VERSION 5.7 ;
  NOWIREEXTENSIONATPIN ON ;
  DIVIDERCHAR "/" ;
  BUSBITCHARS "[]" ;
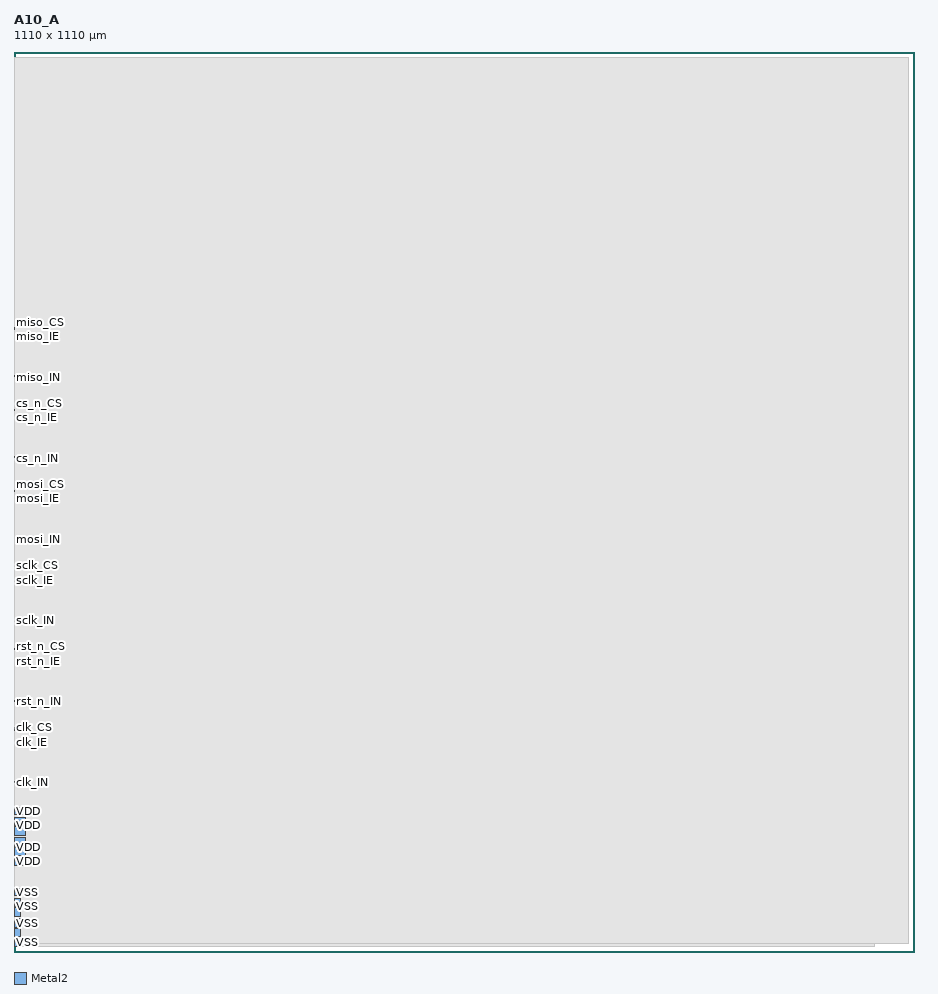
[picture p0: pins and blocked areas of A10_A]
MACRO A10_A
  CLASS BLOCK ;
  FOREIGN A10_A ;
  ORIGIN 0.000 0.000 ;
  SIZE 1110.000 BY 1110.000 ;
  PIN VDD
    DIRECTION INOUT ;
    USE POWER ;
    PORT
      LAYER Metal2 ;
        RECT 0.000 106.360 14.520 115.860 ;
    END
  END VDD
  PIN VDD
    DIRECTION INOUT ;
    USE POWER ;
    PORT
      LAYER Metal2 ;
        RECT 0.000 118.760 14.520 129.010 ;
    END
  END VDD
  PIN VDD
    DIRECTION INOUT ;
    USE POWER ;
    PORT
      LAYER Metal2 ;
        RECT 0.000 130.610 14.520 140.860 ;
    END
  END VDD
  PIN VDD
    DIRECTION INOUT ;
    USE POWER ;
    PORT
      LAYER Metal2 ;
        RECT 0.000 144.140 14.520 154.390 ;
    END
  END VDD
  PIN VDD
    DIRECTION INOUT ;
    USE POWER ;
    PORT
      LAYER Metal2 ;
        RECT 0.000 155.990 14.520 166.240 ;
    END
  END VDD
  PIN VDD
    DIRECTION INOUT ;
    USE POWER ;
    PORT
      LAYER Metal2 ;
        RECT 0.000 169.140 14.520 178.640 ;
    END
  END VDD
  PIN VSS
    DIRECTION INOUT ;
    USE GROUND ;
    PORT
      LAYER Metal2 ;
        RECT 0.000 6.360 7.520 15.860 ;
    END
  END VSS
  PIN VSS
    DIRECTION INOUT ;
    USE GROUND ;
    PORT
      LAYER Metal2 ;
        RECT 0.000 18.760 7.520 29.010 ;
    END
  END VSS
  PIN VSS
    DIRECTION INOUT ;
    USE GROUND ;
    PORT
      LAYER Metal2 ;
        RECT 0.000 30.610 7.520 40.860 ;
    END
  END VSS
  PIN VSS
    DIRECTION INOUT ;
    USE GROUND ;
    PORT
      LAYER Metal2 ;
        RECT 0.000 44.140 7.520 54.390 ;
    END
  END VSS
  PIN VSS
    DIRECTION INOUT ;
    USE GROUND ;
    PORT
      LAYER Metal2 ;
        RECT 0.000 55.990 7.520 66.240 ;
    END
  END VSS
  PIN VSS
    DIRECTION INOUT ;
    USE GROUND ;
    PORT
      LAYER Metal2 ;
        RECT 0.000 69.140 7.520 78.640 ;
    END
  END VSS
  PIN clk_CS
    DIRECTION OUTPUT ;
    USE SIGNAL ;
    ANTENNADIFFAREA 0.360800 ;
    PORT
      LAYER Metal2 ;
        RECT 0.000 276.260 1.000 276.640 ;
    END
  END clk_CS
  PIN clk_IE
    DIRECTION OUTPUT ;
    USE SIGNAL ;
    ANTENNADIFFAREA 0.536800 ;
    PORT
      LAYER Metal2 ;
        RECT 0.000 268.235 1.000 268.615 ;
    END
  END clk_IE
  PIN clk_IN
    DIRECTION INPUT ;
    USE SIGNAL ;
    ANTENNAGATEAREA 1.183000 ;
    ANTENNADIFFAREA 1.231200 ;
    PORT
      LAYER Metal2 ;
        RECT 0.000 208.760 1.000 209.140 ;
    END
  END clk_IN
  PIN clk_OE
    DIRECTION OUTPUT ;
    USE SIGNAL ;
    ANTENNADIFFAREA 0.360800 ;
    PORT
      LAYER Metal2 ;
        RECT 0.000 209.490 1.000 209.870 ;
    END
  END clk_OE
  PIN clk_OUT
    DIRECTION OUTPUT ;
    USE SIGNAL ;
    ANTENNADIFFAREA 0.360800 ;
    PORT
      LAYER Metal2 ;
        RECT 0.000 210.220 1.000 210.600 ;
    END
  END clk_OUT
  PIN clk_PD
    DIRECTION OUTPUT ;
    USE SIGNAL ;
    ANTENNADIFFAREA 0.360800 ;
    PORT
      LAYER Metal2 ;
        RECT 0.000 269.290 1.000 269.670 ;
    END
  END clk_PD
  PIN clk_PU
    DIRECTION OUTPUT ;
    USE SIGNAL ;
    ANTENNADIFFAREA 0.360800 ;
    PORT
      LAYER Metal2 ;
        RECT 0.000 273.655 1.000 274.035 ;
    END
  END clk_PU
  PIN clk_SL
    DIRECTION OUTPUT ;
    USE SIGNAL ;
    ANTENNADIFFAREA 0.360800 ;
    PORT
      LAYER Metal2 ;
        RECT 0.000 210.950 1.000 211.330 ;
    END
  END clk_SL
  PIN cs_n_CS
    DIRECTION OUTPUT ;
    USE SIGNAL ;
    ANTENNADIFFAREA 0.360800 ;
    PORT
      LAYER Metal2 ;
        RECT 0.000 676.260 1.000 676.640 ;
    END
  END cs_n_CS
  PIN cs_n_IE
    DIRECTION OUTPUT ;
    USE SIGNAL ;
    ANTENNADIFFAREA 0.536800 ;
    PORT
      LAYER Metal2 ;
        RECT 0.000 668.235 1.000 668.615 ;
    END
  END cs_n_IE
  PIN cs_n_IN
    DIRECTION INPUT ;
    USE SIGNAL ;
    ANTENNAGATEAREA 0.741000 ;
    ANTENNADIFFAREA 0.410400 ;
    PORT
      LAYER Metal2 ;
        RECT 0.000 608.760 1.000 609.140 ;
    END
  END cs_n_IN
  PIN cs_n_OE
    DIRECTION OUTPUT ;
    USE SIGNAL ;
    ANTENNADIFFAREA 0.360800 ;
    PORT
      LAYER Metal2 ;
        RECT 0.000 609.490 1.000 609.870 ;
    END
  END cs_n_OE
  PIN cs_n_OUT
    DIRECTION OUTPUT ;
    USE SIGNAL ;
    ANTENNADIFFAREA 0.360800 ;
    PORT
      LAYER Metal2 ;
        RECT 0.000 610.220 1.000 610.600 ;
    END
  END cs_n_OUT
  PIN cs_n_PD
    DIRECTION OUTPUT ;
    USE SIGNAL ;
    ANTENNADIFFAREA 0.360800 ;
    PORT
      LAYER Metal2 ;
        RECT 0.000 669.290 1.000 669.670 ;
    END
  END cs_n_PD
  PIN cs_n_PU
    DIRECTION OUTPUT ;
    USE SIGNAL ;
    ANTENNADIFFAREA 0.360800 ;
    PORT
      LAYER Metal2 ;
        RECT 0.000 673.655 1.000 674.035 ;
    END
  END cs_n_PU
  PIN cs_n_SL
    DIRECTION OUTPUT ;
    USE SIGNAL ;
    ANTENNADIFFAREA 0.360800 ;
    PORT
      LAYER Metal2 ;
        RECT 0.000 610.950 1.000 611.330 ;
    END
  END cs_n_SL
  PIN miso_CS
    DIRECTION OUTPUT ;
    USE SIGNAL ;
    ANTENNADIFFAREA 0.360800 ;
    PORT
      LAYER Metal2 ;
        RECT 0.000 776.260 1.000 776.640 ;
    END
  END miso_CS
  PIN miso_IE
    DIRECTION OUTPUT ;
    USE SIGNAL ;
    ANTENNADIFFAREA 0.360800 ;
    PORT
      LAYER Metal2 ;
        RECT 0.000 768.235 1.000 768.615 ;
    END
  END miso_IE
  PIN miso_IN
    DIRECTION INPUT ;
    USE SIGNAL ;
    PORT
      LAYER Metal2 ;
        RECT 0.000 708.760 1.000 709.140 ;
    END
  END miso_IN
  PIN miso_OE
    DIRECTION OUTPUT ;
    USE SIGNAL ;
    ANTENNADIFFAREA 0.536800 ;
    PORT
      LAYER Metal2 ;
        RECT 0.000 709.490 1.000 709.870 ;
    END
  END miso_OE
  PIN miso_OUT
    DIRECTION OUTPUT ;
    USE SIGNAL ;
    ANTENNADIFFAREA 0.897600 ;
    PORT
      LAYER Metal2 ;
        RECT 0.000 710.220 1.000 710.600 ;
    END
  END miso_OUT
  PIN miso_PD
    DIRECTION OUTPUT ;
    USE SIGNAL ;
    ANTENNADIFFAREA 0.360800 ;
    PORT
      LAYER Metal2 ;
        RECT 0.000 769.290 1.000 769.670 ;
    END
  END miso_PD
  PIN miso_PU
    DIRECTION OUTPUT ;
    USE SIGNAL ;
    ANTENNADIFFAREA 0.360800 ;
    PORT
      LAYER Metal2 ;
        RECT 0.000 773.655 1.000 774.035 ;
    END
  END miso_PU
  PIN miso_SL
    DIRECTION OUTPUT ;
    USE SIGNAL ;
    ANTENNADIFFAREA 0.360800 ;
    PORT
      LAYER Metal2 ;
        RECT 0.000 710.950 1.000 711.330 ;
    END
  END miso_SL
  PIN mosi_CS
    DIRECTION OUTPUT ;
    USE SIGNAL ;
    ANTENNADIFFAREA 0.360800 ;
    PORT
      LAYER Metal2 ;
        RECT 0.000 576.260 1.000 576.640 ;
    END
  END mosi_CS
  PIN mosi_IE
    DIRECTION OUTPUT ;
    USE SIGNAL ;
    ANTENNADIFFAREA 0.536800 ;
    PORT
      LAYER Metal2 ;
        RECT 0.000 568.235 1.000 568.615 ;
    END
  END mosi_IE
  PIN mosi_IN
    DIRECTION INPUT ;
    USE SIGNAL ;
    ANTENNAGATEAREA 0.741000 ;
    ANTENNADIFFAREA 0.410400 ;
    PORT
      LAYER Metal2 ;
        RECT 0.000 508.760 1.000 509.140 ;
    END
  END mosi_IN
  PIN mosi_OE
    DIRECTION OUTPUT ;
    USE SIGNAL ;
    ANTENNADIFFAREA 0.360800 ;
    PORT
      LAYER Metal2 ;
        RECT 0.000 509.490 1.000 509.870 ;
    END
  END mosi_OE
  PIN mosi_OUT
    DIRECTION OUTPUT ;
    USE SIGNAL ;
    ANTENNADIFFAREA 0.360800 ;
    PORT
      LAYER Metal2 ;
        RECT 0.000 510.220 1.000 510.600 ;
    END
  END mosi_OUT
  PIN mosi_PD
    DIRECTION OUTPUT ;
    USE SIGNAL ;
    ANTENNADIFFAREA 0.360800 ;
    PORT
      LAYER Metal2 ;
        RECT 0.000 569.290 1.000 569.670 ;
    END
  END mosi_PD
  PIN mosi_PU
    DIRECTION OUTPUT ;
    USE SIGNAL ;
    ANTENNADIFFAREA 0.360800 ;
    PORT
      LAYER Metal2 ;
        RECT 0.000 573.655 1.000 574.035 ;
    END
  END mosi_PU
  PIN mosi_SL
    DIRECTION OUTPUT ;
    USE SIGNAL ;
    ANTENNADIFFAREA 0.360800 ;
    PORT
      LAYER Metal2 ;
        RECT 0.000 510.950 1.000 511.330 ;
    END
  END mosi_SL
  PIN rst_n_CS
    DIRECTION OUTPUT ;
    USE SIGNAL ;
    ANTENNADIFFAREA 0.360800 ;
    PORT
      LAYER Metal2 ;
        RECT 0.000 376.260 1.000 376.640 ;
    END
  END rst_n_CS
  PIN rst_n_IE
    DIRECTION OUTPUT ;
    USE SIGNAL ;
    ANTENNADIFFAREA 0.536800 ;
    PORT
      LAYER Metal2 ;
        RECT 0.000 368.235 1.000 368.615 ;
    END
  END rst_n_IE
  PIN rst_n_IN
    DIRECTION INPUT ;
    USE SIGNAL ;
    ANTENNAGATEAREA 0.498500 ;
    ANTENNADIFFAREA 0.410400 ;
    PORT
      LAYER Metal2 ;
        RECT 0.000 308.760 1.000 309.140 ;
    END
  END rst_n_IN
  PIN rst_n_OE
    DIRECTION OUTPUT ;
    USE SIGNAL ;
    ANTENNADIFFAREA 0.360800 ;
    PORT
      LAYER Metal2 ;
        RECT 0.000 309.490 1.000 309.870 ;
    END
  END rst_n_OE
  PIN rst_n_OUT
    DIRECTION OUTPUT ;
    USE SIGNAL ;
    ANTENNADIFFAREA 0.360800 ;
    PORT
      LAYER Metal2 ;
        RECT 0.000 310.220 1.000 310.600 ;
    END
  END rst_n_OUT
  PIN rst_n_PD
    DIRECTION OUTPUT ;
    USE SIGNAL ;
    ANTENNADIFFAREA 0.360800 ;
    PORT
      LAYER Metal2 ;
        RECT 0.000 369.290 1.000 369.670 ;
    END
  END rst_n_PD
  PIN rst_n_PU
    DIRECTION OUTPUT ;
    USE SIGNAL ;
    ANTENNADIFFAREA 0.360800 ;
    PORT
      LAYER Metal2 ;
        RECT 0.000 373.655 1.000 374.035 ;
    END
  END rst_n_PU
  PIN rst_n_SL
    DIRECTION OUTPUT ;
    USE SIGNAL ;
    ANTENNADIFFAREA 0.360800 ;
    PORT
      LAYER Metal2 ;
        RECT 0.000 310.950 1.000 311.330 ;
    END
  END rst_n_SL
  PIN sclk_CS
    DIRECTION OUTPUT ;
    USE SIGNAL ;
    ANTENNADIFFAREA 0.360800 ;
    PORT
      LAYER Metal2 ;
        RECT 0.000 476.260 1.000 476.640 ;
    END
  END sclk_CS
  PIN sclk_IE
    DIRECTION OUTPUT ;
    USE SIGNAL ;
    ANTENNADIFFAREA 0.536800 ;
    PORT
      LAYER Metal2 ;
        RECT 0.000 468.235 1.000 468.615 ;
    END
  END sclk_IE
  PIN sclk_IN
    DIRECTION INPUT ;
    USE SIGNAL ;
    ANTENNAGATEAREA 1.183000 ;
    ANTENNADIFFAREA 0.410400 ;
    PORT
      LAYER Metal2 ;
        RECT 0.000 408.760 1.000 409.140 ;
    END
  END sclk_IN
  PIN sclk_OE
    DIRECTION OUTPUT ;
    USE SIGNAL ;
    ANTENNADIFFAREA 0.360800 ;
    PORT
      LAYER Metal2 ;
        RECT 0.000 409.490 1.000 409.870 ;
    END
  END sclk_OE
  PIN sclk_OUT
    DIRECTION OUTPUT ;
    USE SIGNAL ;
    ANTENNADIFFAREA 0.360800 ;
    PORT
      LAYER Metal2 ;
        RECT 0.000 410.220 1.000 410.600 ;
    END
  END sclk_OUT
  PIN sclk_PD
    DIRECTION OUTPUT ;
    USE SIGNAL ;
    ANTENNADIFFAREA 0.360800 ;
    PORT
      LAYER Metal2 ;
        RECT 0.000 469.290 1.000 469.670 ;
    END
  END sclk_PD
  PIN sclk_PU
    DIRECTION OUTPUT ;
    USE SIGNAL ;
    ANTENNADIFFAREA 0.360800 ;
    PORT
      LAYER Metal2 ;
        RECT 0.000 473.655 1.000 474.035 ;
    END
  END sclk_PU
  PIN sclk_SL
    DIRECTION OUTPUT ;
    USE SIGNAL ;
    ANTENNADIFFAREA 0.360800 ;
    PORT
      LAYER Metal2 ;
        RECT 0.000 410.950 1.000 411.330 ;
    END
  END sclk_SL
  OBS
      LAYER Nwell ;
        RECT 19.730 23.090 1090.190 1090.190 ;
      LAYER Metal1 ;
        RECT 20.160 23.220 1089.760 1090.060 ;
      LAYER Metal2 ;
        RECT 0.140 776.940 1061.060 1089.950 ;
        RECT 1.300 775.960 1061.060 776.940 ;
        RECT 0.140 774.335 1061.060 775.960 ;
        RECT 1.300 773.355 1061.060 774.335 ;
        RECT 0.140 769.970 1061.060 773.355 ;
        RECT 1.300 768.990 1061.060 769.970 ;
        RECT 0.140 768.915 1061.060 768.990 ;
        RECT 1.300 767.935 1061.060 768.915 ;
        RECT 0.140 711.630 1061.060 767.935 ;
        RECT 1.300 708.460 1061.060 711.630 ;
        RECT 0.140 676.940 1061.060 708.460 ;
        RECT 1.300 675.960 1061.060 676.940 ;
        RECT 0.140 674.335 1061.060 675.960 ;
        RECT 1.300 673.355 1061.060 674.335 ;
        RECT 0.140 669.970 1061.060 673.355 ;
        RECT 1.300 668.990 1061.060 669.970 ;
        RECT 0.140 668.915 1061.060 668.990 ;
        RECT 1.300 667.935 1061.060 668.915 ;
        RECT 0.140 611.630 1061.060 667.935 ;
        RECT 1.300 608.460 1061.060 611.630 ;
        RECT 0.140 576.940 1061.060 608.460 ;
        RECT 1.300 575.960 1061.060 576.940 ;
        RECT 0.140 574.335 1061.060 575.960 ;
        RECT 1.300 573.355 1061.060 574.335 ;
        RECT 0.140 569.970 1061.060 573.355 ;
        RECT 1.300 568.990 1061.060 569.970 ;
        RECT 0.140 568.915 1061.060 568.990 ;
        RECT 1.300 567.935 1061.060 568.915 ;
        RECT 0.140 511.630 1061.060 567.935 ;
        RECT 1.300 508.460 1061.060 511.630 ;
        RECT 0.140 476.940 1061.060 508.460 ;
        RECT 1.300 475.960 1061.060 476.940 ;
        RECT 0.140 474.335 1061.060 475.960 ;
        RECT 1.300 473.355 1061.060 474.335 ;
        RECT 0.140 469.970 1061.060 473.355 ;
        RECT 1.300 468.990 1061.060 469.970 ;
        RECT 0.140 468.915 1061.060 468.990 ;
        RECT 1.300 467.935 1061.060 468.915 ;
        RECT 0.140 411.630 1061.060 467.935 ;
        RECT 1.300 408.460 1061.060 411.630 ;
        RECT 0.140 376.940 1061.060 408.460 ;
        RECT 1.300 375.960 1061.060 376.940 ;
        RECT 0.140 374.335 1061.060 375.960 ;
        RECT 1.300 373.355 1061.060 374.335 ;
        RECT 0.140 369.970 1061.060 373.355 ;
        RECT 1.300 368.990 1061.060 369.970 ;
        RECT 0.140 368.915 1061.060 368.990 ;
        RECT 1.300 367.935 1061.060 368.915 ;
        RECT 0.140 311.630 1061.060 367.935 ;
        RECT 1.300 308.460 1061.060 311.630 ;
        RECT 0.140 276.940 1061.060 308.460 ;
        RECT 1.300 275.960 1061.060 276.940 ;
        RECT 0.140 274.335 1061.060 275.960 ;
        RECT 1.300 273.355 1061.060 274.335 ;
        RECT 0.140 269.970 1061.060 273.355 ;
        RECT 1.300 268.990 1061.060 269.970 ;
        RECT 0.140 268.915 1061.060 268.990 ;
        RECT 1.300 267.935 1061.060 268.915 ;
        RECT 0.140 211.630 1061.060 267.935 ;
        RECT 1.300 208.460 1061.060 211.630 ;
        RECT 0.140 178.940 1061.060 208.460 ;
        RECT 14.820 168.840 1061.060 178.940 ;
        RECT 0.140 166.540 1061.060 168.840 ;
        RECT 14.820 155.690 1061.060 166.540 ;
        RECT 0.140 154.690 1061.060 155.690 ;
        RECT 14.820 143.840 1061.060 154.690 ;
        RECT 0.140 141.160 1061.060 143.840 ;
        RECT 14.820 130.310 1061.060 141.160 ;
        RECT 0.140 129.310 1061.060 130.310 ;
        RECT 14.820 118.460 1061.060 129.310 ;
        RECT 0.140 116.160 1061.060 118.460 ;
        RECT 14.820 106.060 1061.060 116.160 ;
        RECT 0.140 78.940 1061.060 106.060 ;
        RECT 7.820 68.840 1061.060 78.940 ;
        RECT 0.140 66.540 1061.060 68.840 ;
        RECT 7.820 55.690 1061.060 66.540 ;
        RECT 0.140 54.690 1061.060 55.690 ;
        RECT 7.820 43.840 1061.060 54.690 ;
        RECT 0.140 41.160 1061.060 43.840 ;
        RECT 7.820 30.310 1061.060 41.160 ;
        RECT 0.140 29.310 1061.060 30.310 ;
        RECT 7.820 18.460 1061.060 29.310 ;
        RECT 0.140 16.160 1061.060 18.460 ;
        RECT 7.820 6.360 1061.060 16.160 ;
      LAYER Metal3 ;
        RECT 0.090 6.360 1061.110 1089.900 ;
      LAYER Metal4 ;
        RECT 0.140 10.520 1102.760 1102.760 ;
      LAYER Metal5 ;
        RECT 0.060 10.520 1102.760 1102.760 ;
  END
END A10_A
END LIBRARY

